VERSION 5.8 ;
BUSBITCHARS "[]" ;
DIVIDERCHAR "/" ;

PROPERTYDEFINITIONS
  MACRO CatenaDesignType STRING ;
  LAYER LEF58_TYPE STRING ;
  LAYER LEF58_SPACING STRING ;
  LAYER LEF58_WIDTH STRING ;
END PROPERTYDEFINITIONS

UNITS
  TIME NANOSECONDS 1 ;
  CAPACITANCE PICOFARADS 1 ;
  RESISTANCE OHMS 1 ;
  DATABASE MICRONS 1000 ;
END UNITS
MANUFACTURINGGRID 0.005 ;
LAYER OVERLAP
  TYPE OVERLAP ;
END OVERLAP

LAYER dnwell
  TYPE MASTERSLICE ;
END dnwell

LAYER pwell
  TYPE MASTERSLICE ;
  PROPERTY LEF58_TYPE "TYPE PWELL ;" ;
END pwell

LAYER nwell
  TYPE MASTERSLICE ;
  PROPERTY LEF58_TYPE "TYPE NWELL ;" ;
  PROPERTY LEF58_SPACING "SPACING 1.27 ;" ;
  PROPERTY LEF58_WIDTH "WIDTH 0.84 ;" ;
END nwell

LAYER diff
  TYPE MASTERSLICE ;
  PROPERTY LEF58_TYPE "TYPE DIFFUSION ;" ;
  PROPERTY LEF58_SPACING "SPACING 0.27 ;" ;
  PROPERTY LEF58_WIDTH "WIDTH 0.15 ;" ;
END diff

LAYER tap
  TYPE MASTERSLICE ;
  PROPERTY LEF58_TYPE "TYPE DIFFUSION ;" ;
  PROPERTY LEF58_SPACING "SPACING 0.27 ;" ;
  PROPERTY LEF58_WIDTH "WIDTH 0.15 ;" ;
END tap

LAYER nsdm
  TYPE IMPLANT ;
  WIDTH 0.38 ;
  SPACING 0.38 ;
  AREA 0.265 ;
END nsdm

LAYER psdm
  TYPE IMPLANT ;
  WIDTH 0.38 ;
  SPACING 0.38 ;
  AREA 0.255 ;
END psdm

LAYER poly
  TYPE MASTERSLICE ;
END poly

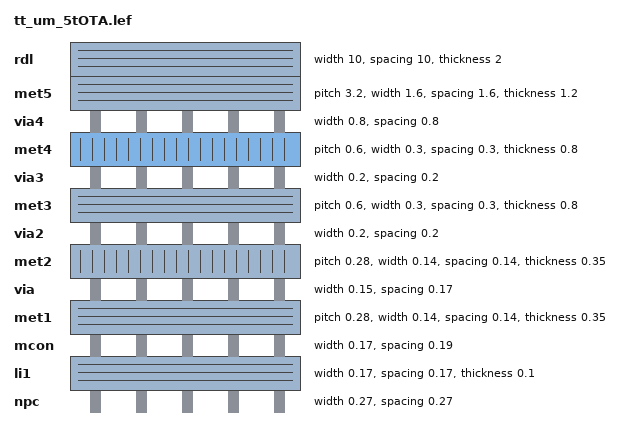
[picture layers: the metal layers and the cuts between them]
LAYER npc
  TYPE CUT ;
  SPACING 0.27 ;
  WIDTH 0.27 ;
  ANTENNAMODEL OXIDE1 ;
END npc

LAYER licon1
  TYPE MASTERSLICE ;
  PROPERTY LEF58_TYPE "TYPE MEOL ;" ;
END licon1

LAYER li1
  TYPE ROUTING ;
  DIRECTION HORIZONTAL ;
  WIDTH 0.17 ;
  AREA 0.056 ;
  SPACING 0.17 ;
  SPACING 0.17 SAMENET ;
  RESISTANCE RPERSQ 12.2 ;
  CAPACITANCE CPERSQDIST 3.69e-05 ;
  THICKNESS 0.1 ;
  EDGECAPACITANCE 3.26e-06 ;
  ANTENNAMODEL OXIDE1 ;
    ANTENNASIDEAREARATIO 75 ;
    ANTENNADIFFSIDEAREARATIO PWL ( ( 0 75 ) ( 0.0125 75 ) ( 0.0225 85.125 ) ( 22.5 10200 ) ) ;
END li1

LAYER mcon
  TYPE CUT ;
  SPACING 0.19 ;
  WIDTH 0.17 ;
  ENCLOSURE BELOW 0 0 ;
  ENCLOSURE ABOVE 0.03 0.06 ;
  ANTENNAMODEL OXIDE1 ;
    ANTENNAAREARATIO 3 ;
    ANTENNADIFFAREARATIO PWL ( ( 0 3 ) ( 0.0125 3 ) ( 0.0225 3.405 ) ( 22.5 408 ) ) ;
  DCCURRENTDENSITY AVERAGE 0.36 ;
END mcon

LAYER met1
  TYPE ROUTING ;
  DIRECTION HORIZONTAL ;
  PITCH 0.28 0.28 ;
  WIDTH 0.14 ;
  OFFSET 0.14 0.14 ;
  AREA 0.083 ;
  SPACING 0.14 ;
  SPACING 0.28 RANGE 3.005 10000 ;
  SPACING 0.14 SAMENET ;
  SPACING 0.28 RANGE 3.005 10000 INFLUENCE 0.28 ;
  MAXWIDTH 4 ;
  MINENCLOSEDAREA 0.14 ;
  RESISTANCE RPERSQ 0.125 ;
  CAPACITANCE CPERSQDIST 2.58e-05 ;
  THICKNESS 0.35 ;
  EDGECAPACITANCE 1.79e-06 ;
  ANTENNAMODEL OXIDE1 ;
    ANTENNASIDEAREARATIO 400 ;
    ANTENNADIFFSIDEAREARATIO PWL ( ( 0 400 ) ( 0.0125 400 ) ( 0.0225 2609 ) ( 22.5 11600 ) ) ;
  ACCURRENTDENSITY RMS 6.1 ;
  DCCURRENTDENSITY AVERAGE 2.8 ;
END met1

LAYER via
  TYPE CUT ;
  SPACING 0.17 ;
  WIDTH 0.15 ;
  ENCLOSURE BELOW 0.055 0.085 ;
  ENCLOSURE ABOVE 0.055 0.085 ;
  ANTENNAMODEL OXIDE1 ;
    ANTENNAAREARATIO 6 ;
    ANTENNADIFFAREARATIO PWL ( ( 0 6 ) ( 0.0125 6 ) ( 0.0225 6.81 ) ( 22.5 816 ) ) ;
  DCCURRENTDENSITY AVERAGE 0.29 ;
END via

LAYER met2
  TYPE ROUTING ;
  DIRECTION VERTICAL ;
  PITCH 0.28 0.28 ;
  WIDTH 0.14 ;
  OFFSET 0.14 0.14 ;
  AREA 0.0676 ;
  SPACING 0.14 ;
  SPACING 0.28 RANGE 3.005 10000 ;
  SPACING 0.14 SAMENET ;
  SPACING 0.28 RANGE 3.005 10000 INFLUENCE 0.28 ;
  MAXWIDTH 4 ;
  MINENCLOSEDAREA 0.14 ;
  RESISTANCE RPERSQ 0.125 ;
  CAPACITANCE CPERSQDIST 1.75e-05 ;
  THICKNESS 0.35 ;
  EDGECAPACITANCE 1.22e-06 ;
  ANTENNAMODEL OXIDE1 ;
    ANTENNASIDEAREARATIO 400 ;
    ANTENNADIFFSIDEAREARATIO PWL ( ( 0 400 ) ( 0.0125 400 ) ( 0.0225 2609 ) ( 22.5 11600 ) ) ;
  ACCURRENTDENSITY RMS 6.1 ;
  DCCURRENTDENSITY AVERAGE 2.8 ;
END met2

LAYER via2
  TYPE CUT ;
  SPACING 0.2 ;
  WIDTH 0.2 ;
  ENCLOSURE BELOW 0.04 0.085 ;
  ENCLOSURE ABOVE 0.065 0.065 ;
  ANTENNAMODEL OXIDE1 ;
    ANTENNAAREARATIO 6 ;
    ANTENNADIFFAREARATIO PWL ( ( 0 6 ) ( 0.0125 6 ) ( 0.0225 6.81 ) ( 22.5 816 ) ) ;
  DCCURRENTDENSITY AVERAGE 0.48 ;
END via2

LAYER met3
  TYPE ROUTING ;
  DIRECTION HORIZONTAL ;
  PITCH 0.6 0.6 ;
  WIDTH 0.3 ;
  OFFSET 0.3 0.3 ;
  AREA 0.24 ;
  SPACING 0.3 ;
  SPACING 0.4 RANGE 3.005 10000 ;
  SPACING 0.3 SAMENET ;
  SPACING 0.4 RANGE 3.005 10000 INFLUENCE 0.4 ;
  MAXWIDTH 4 ;
  MINENCLOSEDAREA 0.2 ;
  RESISTANCE RPERSQ 0.047 ;
  CAPACITANCE CPERSQDIST 1.26e-05 ;
  THICKNESS 0.8 ;
  EDGECAPACITANCE 1.86e-06 ;
  ANTENNAMODEL OXIDE1 ;
    ANTENNASIDEAREARATIO 400 ;
    ANTENNADIFFSIDEAREARATIO PWL ( ( 0 400 ) ( 0.0125 400 ) ( 0.0225 2609 ) ( 22.5 11600 ) ) ;
  ACCURRENTDENSITY RMS 14.9 ;
  DCCURRENTDENSITY AVERAGE 6.8 ;
END met3

LAYER via3
  TYPE CUT ;
  SPACING 0.2 ;
  WIDTH 0.2 ;
  ENCLOSURE BELOW 0.06 0.09 ;
  ENCLOSURE ABOVE 0.065 0.065 ;
  ANTENNAMODEL OXIDE1 ;
    ANTENNAAREARATIO 6 ;
    ANTENNADIFFAREARATIO PWL ( ( 0 6 ) ( 0.0125 6 ) ( 0.0225 6.81 ) ( 22.5 816 ) ) ;
  DCCURRENTDENSITY AVERAGE 0.48 ;
END via3

LAYER met4
  TYPE ROUTING ;
  DIRECTION VERTICAL ;
  PITCH 0.6 0.6 ;
  WIDTH 0.3 ;
  OFFSET 0.3 0.3 ;
  AREA 0.24 ;
  SPACING 0.3 ;
  SPACING 0.4 RANGE 3.005 10000 ;
  SPACING 0.3 SAMENET ;
  SPACING 0.4 RANGE 3.005 10000 INFLUENCE 0.4 ;
  MAXWIDTH 10 ;
  MINENCLOSEDAREA 0.2 ;
  RESISTANCE RPERSQ 0.047 ;
  CAPACITANCE CPERSQDIST 8.67e-06 ;
  THICKNESS 0.8 ;
  EDGECAPACITANCE 1.29e-06 ;
  ANTENNAMODEL OXIDE1 ;
    ANTENNASIDEAREARATIO 400 ;
    ANTENNADIFFSIDEAREARATIO PWL ( ( 0 400 ) ( 0.0125 400 ) ( 0.0225 2609 ) ( 22.5 11600 ) ) ;
  ACCURRENTDENSITY RMS 14.9 ;
  DCCURRENTDENSITY AVERAGE 6.8 ;
END met4

LAYER via4
  TYPE CUT ;
  SPACING 0.8 ;
  WIDTH 0.8 ;
  ENCLOSURE BELOW 0.19 0.19 ;
  ENCLOSURE ABOVE 0.31 0.31 ;
  ANTENNAMODEL OXIDE1 ;
    ANTENNAAREARATIO 6 ;
    ANTENNADIFFAREARATIO PWL ( ( 0 6 ) ( 0.0125 6 ) ( 0.0225 6.81 ) ( 22.5 816 ) ) ;
  DCCURRENTDENSITY AVERAGE 2.49 ;
END via4

LAYER met5
  TYPE ROUTING ;
  DIRECTION HORIZONTAL ;
  PITCH 3.2 3.2 ;
  WIDTH 1.6 ;
  OFFSET 1.6 1.6 ;
  AREA 4 ;
  SPACING 1.6 ;
  SPACING 1.6 SAMENET ;
  RESISTANCE RPERSQ 0.0285 ;
  CAPACITANCE CPERSQDIST 6.48e-06 ;
  THICKNESS 1.2 ;
  EDGECAPACITANCE 4.96e-06 ;
  ANTENNAMODEL OXIDE1 ;
    ANTENNASIDEAREARATIO 400 ;
    ANTENNADIFFSIDEAREARATIO PWL ( ( 0 400 ) ( 0.0125 400 ) ( 0.0225 2609 ) ( 22.5 11600 ) ) ;
  ACCURRENTDENSITY RMS 22.34 ;
  DCCURRENTDENSITY AVERAGE 10.17 ;
END met5

LAYER rdl
  TYPE ROUTING ;
  DIRECTION HORIZONTAL ;
  WIDTH 10 ;
  SPACING 10 ;
  RESISTANCE RPERSQ 0.005 ;
  CAPACITANCE CPERSQDIST 2.66e-06 ;
  THICKNESS 2 ;
  EDGECAPACITANCE 6.2e-06 ;
  ANTENNAMODEL OXIDE1 ;
END rdl

VIARULE M4M5_C GENERATE DEFAULT
  LAYER met5 ;
    ENCLOSURE 0.31 0.31 ;
  LAYER met4 ;
    ENCLOSURE 0.19 0.19 ;
  LAYER via4 ;
    RECT -0.4 -0.4 0.4 0.4 ;
    SPACING 1.6 BY 1.6 ;
    RESISTANCE 0.380000 ;
END M4M5_C

VIARULE M3M4_C GENERATE DEFAULT
  LAYER met4 ;
    ENCLOSURE 0.065 0.065 ;
  LAYER met3 ;
    ENCLOSURE 0.06 0.09 ;
  LAYER via3 ;
    RECT -0.1 -0.1 0.1 0.1 ;
    SPACING 0.4 BY 0.4 ;
    RESISTANCE 3.410000 ;
END M3M4_C

VIARULE M2M3_C GENERATE DEFAULT
  LAYER met3 ;
    ENCLOSURE 0.065 0.065 ;
  LAYER met2 ;
    ENCLOSURE 0.04 0.085 ;
  LAYER via2 ;
    RECT -0.1 -0.1 0.1 0.1 ;
    SPACING 0.4 BY 0.4 ;
    RESISTANCE 3.410000 ;
END M2M3_C

VIARULE M1M2_C GENERATE DEFAULT
  LAYER met2 ;
    ENCLOSURE 0.055 0.085 ;
  LAYER met1 ;
    ENCLOSURE 0.055 0.085 ;
  LAYER via ;
    RECT -0.075 -0.075 0.075 0.075 ;
    SPACING 0.32 BY 0.32 ;
    RESISTANCE 4.500000 ;
END M1M2_C

VIARULE L1M1_C GENERATE DEFAULT
  LAYER met1 ;
    ENCLOSURE 0.03 0.06 ;
  LAYER li1 ;
    ENCLOSURE 0 0.08 ;
  LAYER mcon ;
    RECT -0.085 -0.085 0.085 0.085 ;
    SPACING 0.36 BY 0.36 ;
    RESISTANCE 9.300000 ;
END L1M1_C

VIA M1M2_C_0
  VIARULE M1M2_C ;
  CUTSIZE 0.15 0.15 ;
  LAYERS met1 via met2 ;
  CUTSPACING 0.17 0.17 ;
  ENCLOSURE 0.055 0.085 0.055 0.085 ;
  ROWCOL 1 1 ;
END M1M2_C_0

VIA M2M3_C_1
  VIARULE M2M3_C ;
  CUTSIZE 0.2 0.2 ;
  LAYERS met2 via2 met3 ;
  CUTSPACING 0.2 0.2 ;
  ENCLOSURE 0.04 0.085 0.065 0.065 ;
  ROWCOL 1 1 ;
END M2M3_C_1

VIA M1M2_C_2
  VIARULE M1M2_C ;
  CUTSIZE 0.15 0.15 ;
  LAYERS met1 via met2 ;
  CUTSPACING 0.17 0.17 ;
  ENCLOSURE 0.055 0.085 0.055 0.085 ;
  ROWCOL 4 3 ;
END M1M2_C_2

VIA M2M3_C_3
  VIARULE M2M3_C ;
  CUTSIZE 0.2 0.2 ;
  LAYERS met2 via2 met3 ;
  CUTSPACING 0.2 0.2 ;
  ENCLOSURE 0.04 0.085 0.065 0.065 ;
  ROWCOL 3 3 ;
END M2M3_C_3

VIA M3M4_C_4
  VIARULE M3M4_C ;
  CUTSIZE 0.2 0.2 ;
  LAYERS met3 via3 met4 ;
  CUTSPACING 0.2 0.2 ;
  ENCLOSURE 0.06 0.09 0.065 0.065 ;
  ROWCOL 1 1 ;
END M3M4_C_4

VIA M3M4_C_5
  VIARULE M3M4_C ;
  CUTSIZE 0.2 0.2 ;
  LAYERS met3 via3 met4 ;
  CUTSPACING 0.2 0.2 ;
  ENCLOSURE 0.06 0.09 0.065 0.065 ;
  ROWCOL 3 3 ;
END M3M4_C_5

VIA M3M4_C_6
  VIARULE M3M4_C ;
  CUTSIZE 0.2 0.2 ;
  LAYERS met3 via3 met4 ;
  CUTSPACING 0.2 0.2 ;
  ENCLOSURE 0.06 0.09 0.065 0.065 ;
  ROWCOL 2 2 ;
END M3M4_C_6

VIA M2M3_C_7
  VIARULE M2M3_C ;
  CUTSIZE 0.2 0.2 ;
  LAYERS met2 via2 met3 ;
  CUTSPACING 0.2 0.2 ;
  ENCLOSURE 0.04 0.085 0.065 0.065 ;
  ROWCOL 2 2 ;
END M2M3_C_7

VIA M1M2_C_8
  VIARULE M1M2_C ;
  CUTSIZE 0.15 0.15 ;
  LAYERS met1 via met2 ;
  CUTSPACING 0.17 0.17 ;
  ENCLOSURE 0.055 0.085 0.055 0.085 ;
  ROWCOL 2 2 ;
END M1M2_C_8

VIA M1M2_C_9
  VIARULE M1M2_C ;
  CUTSIZE 0.15 0.15 ;
  LAYERS met1 via met2 ;
  CUTSPACING 0.17 0.17 ;
  ENCLOSURE 0.055 0.085 0.055 0.085 ;
  ROWCOL 1 1 ;
END M1M2_C_9

VIA M1M2_C_10
  VIARULE M1M2_C ;
  CUTSIZE 0.15 0.15 ;
  LAYERS met1 via met2 ;
  CUTSPACING 0.17 0.17 ;
  ENCLOSURE 0.055 0.085 0.055 0.085 ;
  ROWCOL 1 2 ;
END M1M2_C_10

VIA M1M2_C_11
  VIARULE M1M2_C ;
  CUTSIZE 0.15 0.15 ;
  LAYERS met1 via met2 ;
  CUTSPACING 0.17 0.17 ;
  ENCLOSURE 0.055 0.085 0.055 0.085 ;
  ROWCOL 2 1 ;
END M1M2_C_11

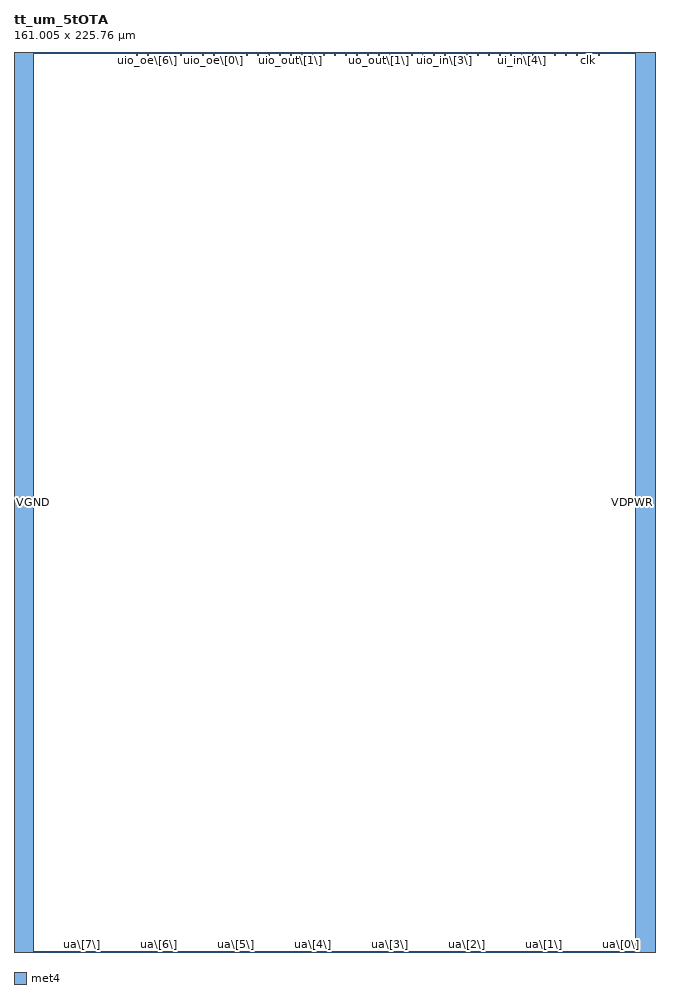
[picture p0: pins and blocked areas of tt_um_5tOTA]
MACRO tt_um_5tOTA
  CLASS BLOCK SOFT ;
  ORIGIN 0.005 0 ;
  FOREIGN tt_um_5tOTA -0.005 0 ;
  SIZE 161.005 BY 225.76 ;
  PIN clk
    DIRECTION INPUT ;
    USE SIGNAL ;
    PORT
      LAYER met4 ;
        RECT 143.83 224.76 144.13 225.76 ;
    END
  END clk
  PIN ena
    DIRECTION INOUT ;
    USE SIGNAL ;
    PORT
      LAYER met4 ;
        RECT 146.59 224.76 146.89 225.76 ;
    END
  END ena
  PIN rst_n
    DIRECTION INPUT ;
    USE SIGNAL ;
    PORT
      LAYER met4 ;
        RECT 141.07 224.76 141.37 225.76 ;
    END
  END rst_n
  PIN ua\[0\]
    DIRECTION INPUT ;
    USE SIGNAL ;
    PORT
      LAYER met4 ;
        RECT 151.81 0 152.71 1 ;
    END
  END ua\[0\]
  PIN ua\[2\]
    DIRECTION INPUT ;
    USE SIGNAL ;
    PORT
      LAYER met4 ;
        RECT 113.17 0 114.07 1 ;
    END
  END ua\[2\]
  PIN ua\[1\]
    DIRECTION INPUT ;
    USE SIGNAL ;
    PORT
      LAYER met4 ;
        RECT 132.495 0 133.395 1 ;
    END
  END ua\[1\]
  PIN ua\[4\]
    DIRECTION INOUT ;
    USE SIGNAL ;
    PORT
      LAYER met4 ;
        RECT 74.53 0 75.43 1 ;
    END
  END ua\[4\]
  PIN ua\[5\]
    DIRECTION INOUT ;
    USE SIGNAL ;
    PORT
      LAYER met4 ;
        RECT 55.21 0 56.11 1 ;
    END
  END ua\[5\]
  PIN ua\[6\]
    DIRECTION INOUT ;
    USE SIGNAL ;
    PORT
      LAYER met4 ;
        RECT 35.89 0 36.79 1 ;
    END
  END ua\[6\]
  PIN ua\[7\]
    DIRECTION INOUT ;
    USE SIGNAL ;
    PORT
      LAYER met4 ;
        RECT 16.57 0 17.47 1 ;
    END
  END ua\[7\]
  PIN ui_in\[0\]
    DIRECTION INPUT ;
    USE SIGNAL ;
    PORT
      LAYER met4 ;
        RECT 138.31 224.76 138.61 225.76 ;
    END
  END ui_in\[0\]
  PIN ui_in\[1\]
    DIRECTION INPUT ;
    USE SIGNAL ;
    PORT
      LAYER met4 ;
        RECT 135.55 224.76 135.85 225.76 ;
    END
  END ui_in\[1\]
  PIN ui_in\[2\]
    DIRECTION INPUT ;
    USE SIGNAL ;
    PORT
      LAYER met4 ;
        RECT 132.79 224.76 133.09 225.76 ;
    END
  END ui_in\[2\]
  PIN ui_in\[3\]
    DIRECTION INPUT ;
    USE SIGNAL ;
    PORT
      LAYER met4 ;
        RECT 130.03 224.76 130.33 225.76 ;
    END
  END ui_in\[3\]
  PIN ui_in\[4\]
    DIRECTION INPUT ;
    USE SIGNAL ;
    PORT
      LAYER met4 ;
        RECT 127.27 224.76 127.57 225.76 ;
    END
  END ui_in\[4\]
  PIN ui_in\[5\]
    DIRECTION INPUT ;
    USE SIGNAL ;
    PORT
      LAYER met4 ;
        RECT 124.51 224.76 124.81 225.76 ;
    END
  END ui_in\[5\]
  PIN ui_in\[6\]
    DIRECTION INPUT ;
    USE SIGNAL ;
    PORT
      LAYER met4 ;
        RECT 121.75 224.76 122.05 225.76 ;
    END
  END ui_in\[6\]
  PIN ui_in\[7\]
    DIRECTION INPUT ;
    USE SIGNAL ;
    PORT
      LAYER met4 ;
        RECT 118.99 224.76 119.29 225.76 ;
    END
  END ui_in\[7\]
  PIN uio_in\[1\]
    DIRECTION INPUT ;
    USE SIGNAL ;
    PORT
      LAYER met4 ;
        RECT 113.47 224.76 113.77 225.76 ;
    END
  END uio_in\[1\]
  PIN uio_in\[0\]
    DIRECTION INPUT ;
    USE SIGNAL ;
    PORT
      LAYER met4 ;
        RECT 116.23 224.76 116.53 225.76 ;
    END
  END uio_in\[0\]
  PIN uio_in\[2\]
    DIRECTION INPUT ;
    USE SIGNAL ;
    PORT
      LAYER met4 ;
        RECT 110.71 224.76 111.01 225.76 ;
    END
  END uio_in\[2\]
  PIN uio_in\[3\]
    DIRECTION INPUT ;
    USE SIGNAL ;
    PORT
      LAYER met4 ;
        RECT 107.95 224.76 108.25 225.76 ;
    END
  END uio_in\[3\]
  PIN uio_in\[4\]
    DIRECTION INPUT ;
    USE SIGNAL ;
    PORT
      LAYER met4 ;
        RECT 105.19 224.76 105.49 225.76 ;
    END
  END uio_in\[4\]
  PIN uio_in\[5\]
    DIRECTION INPUT ;
    USE SIGNAL ;
    PORT
      LAYER met4 ;
        RECT 102.43 224.76 102.73 225.76 ;
    END
  END uio_in\[5\]
  PIN uio_in\[6\]
    DIRECTION INPUT ;
    USE SIGNAL ;
    PORT
      LAYER met4 ;
        RECT 99.67 224.76 99.97 225.76 ;
    END
  END uio_in\[6\]
  PIN uio_in\[7\]
    DIRECTION INPUT ;
    USE SIGNAL ;
    PORT
      LAYER met4 ;
        RECT 96.91 224.76 97.21 225.76 ;
    END
  END uio_in\[7\]
  PIN uo_out\[0\]
    DIRECTION OUTPUT ;
    USE SIGNAL ;
    PORT
      LAYER met4 ;
        RECT 94.15 224.76 94.45 225.76 ;
    END
  END uo_out\[0\]
  PIN uio_oe\[1\]
    DIRECTION OUTPUT ;
    USE SIGNAL ;
    PORT
      LAYER met4 ;
        RECT 47.23 224.76 47.53 225.76 ;
    END
  END uio_oe\[1\]
  PIN uio_oe\[2\]
    DIRECTION OUTPUT ;
    USE SIGNAL ;
    PORT
      LAYER met4 ;
        RECT 44.47 224.76 44.77 225.76 ;
    END
  END uio_oe\[2\]
  PIN uio_oe\[3\]
    DIRECTION OUTPUT ;
    USE SIGNAL ;
    PORT
      LAYER met4 ;
        RECT 41.71 224.76 42.01 225.76 ;
    END
  END uio_oe\[3\]
  PIN uio_oe\[4\]
    DIRECTION OUTPUT ;
    USE SIGNAL ;
    PORT
      LAYER met4 ;
        RECT 38.95 224.76 39.25 225.76 ;
    END
  END uio_oe\[4\]
  PIN uio_oe\[5\]
    DIRECTION OUTPUT ;
    USE SIGNAL ;
    PORT
      LAYER met4 ;
        RECT 36.19 224.76 36.49 225.76 ;
    END
  END uio_oe\[5\]
  PIN uio_oe\[6\]
    DIRECTION OUTPUT ;
    USE SIGNAL ;
    PORT
      LAYER met4 ;
        RECT 33.43 224.76 33.73 225.76 ;
    END
  END uio_oe\[6\]
  PIN uio_oe\[7\]
    DIRECTION OUTPUT ;
    USE SIGNAL ;
    PORT
      LAYER met4 ;
        RECT 30.67 224.76 30.97 225.76 ;
    END
  END uio_oe\[7\]
  PIN uio_out\[1\]
    DIRECTION OUTPUT ;
    USE SIGNAL ;
    PORT
      LAYER met4 ;
        RECT 69.31 224.76 69.61 225.76 ;
    END
  END uio_out\[1\]
  PIN uio_out\[2\]
    DIRECTION OUTPUT ;
    USE SIGNAL ;
    PORT
      LAYER met4 ;
        RECT 66.55 224.76 66.85 225.76 ;
    END
  END uio_out\[2\]
  PIN uio_out\[3\]
    DIRECTION OUTPUT ;
    USE SIGNAL ;
    PORT
      LAYER met4 ;
        RECT 63.79 224.76 64.09 225.76 ;
    END
  END uio_out\[3\]
  PIN uio_out\[4\]
    DIRECTION OUTPUT ;
    USE SIGNAL ;
    PORT
      LAYER met4 ;
        RECT 61.03 224.76 61.33 225.76 ;
    END
  END uio_out\[4\]
  PIN uio_out\[5\]
    DIRECTION OUTPUT ;
    USE SIGNAL ;
    PORT
      LAYER met4 ;
        RECT 58.27 224.76 58.57 225.76 ;
    END
  END uio_out\[5\]
  PIN uio_out\[6\]
    DIRECTION OUTPUT ;
    USE SIGNAL ;
    PORT
      LAYER met4 ;
        RECT 55.51 224.76 55.81 225.76 ;
    END
  END uio_out\[6\]
  PIN uio_out\[7\]
    DIRECTION OUTPUT ;
    USE SIGNAL ;
    PORT
      LAYER met4 ;
        RECT 52.75 224.76 53.05 225.76 ;
    END
  END uio_out\[7\]
  PIN uio_oe\[0\]
    DIRECTION OUTPUT ;
    USE SIGNAL ;
    PORT
      LAYER met4 ;
        RECT 49.99 224.76 50.29 225.76 ;
    END
  END uio_oe\[0\]
  PIN uo_out\[1\]
    DIRECTION OUTPUT ;
    USE SIGNAL ;
    PORT
      LAYER met4 ;
        RECT 91.39 224.76 91.69 225.76 ;
    END
  END uo_out\[1\]
  PIN uo_out\[2\]
    DIRECTION OUTPUT ;
    USE SIGNAL ;
    PORT
      LAYER met4 ;
        RECT 88.63 224.76 88.93 225.76 ;
    END
  END uo_out\[2\]
  PIN uo_out\[3\]
    DIRECTION OUTPUT ;
    USE SIGNAL ;
    PORT
      LAYER met4 ;
        RECT 85.87 224.76 86.17 225.76 ;
    END
  END uo_out\[3\]
  PIN uo_out\[4\]
    DIRECTION OUTPUT ;
    USE SIGNAL ;
    PORT
      LAYER met4 ;
        RECT 83.11 224.76 83.41 225.76 ;
    END
  END uo_out\[4\]
  PIN uo_out\[5\]
    DIRECTION OUTPUT ;
    USE SIGNAL ;
    PORT
      LAYER met4 ;
        RECT 80.35 224.76 80.65 225.76 ;
    END
  END uo_out\[5\]
  PIN uo_out\[6\]
    DIRECTION OUTPUT ;
    USE SIGNAL ;
    PORT
      LAYER met4 ;
        RECT 77.59 224.76 77.89 225.76 ;
    END
  END uo_out\[6\]
  PIN uo_out\[7\]
    DIRECTION OUTPUT ;
    USE SIGNAL ;
    PORT
      LAYER met4 ;
        RECT 74.83 224.76 75.13 225.76 ;
    END
  END uo_out\[7\]
  PIN uio_out\[0\]
    DIRECTION OUTPUT ;
    USE SIGNAL ;
    PORT
      LAYER met4 ;
        RECT 72.07 224.76 72.37 225.76 ;
    END
  END uio_out\[0\]
  PIN VDPWR
    DIRECTION INPUT ;
    USE POWER ;
    PORT
      LAYER met4 ;
        RECT 156 0 161 225.76 ;
    END
  END VDPWR
  PIN ua\[3\]
    DIRECTION OUTPUT ;
    USE SIGNAL ;
    PORT
      LAYER met4 ;
        RECT 93.85 0 94.75 1 ;
    END
  END ua\[3\]
  PIN VGND
    DIRECTION INPUT ;
    USE GROUND ;
    PORT
      LAYER met4 ;
        RECT 0 0 5 225.76 ;
    END
  END VGND
  PROPERTY CatenaDesignType "asic" ;
END tt_um_5tOTA

END LIBRARY
